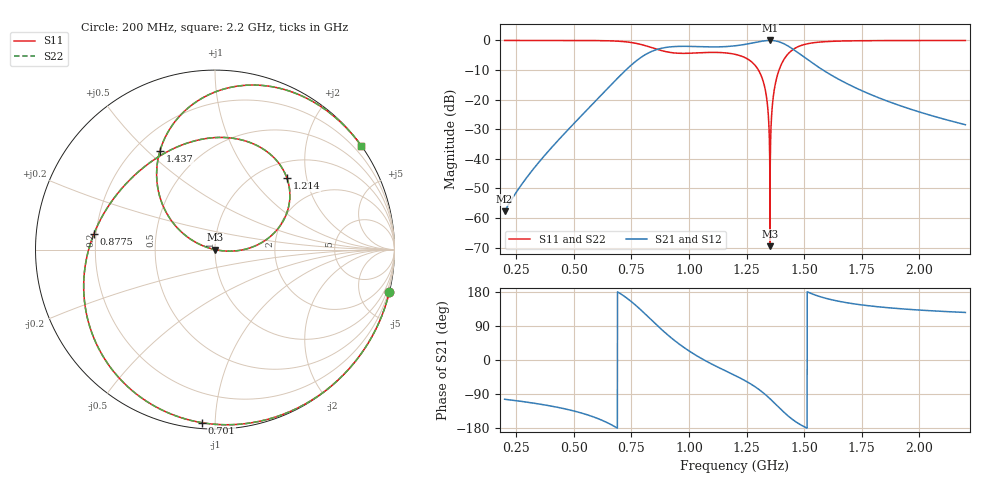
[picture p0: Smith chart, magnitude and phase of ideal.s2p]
! SIMULATED ideal lumped circuit; not measured
# Hz S RI R 50
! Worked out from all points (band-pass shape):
!   4001 points, 200 MHz to 2.2 GHz, reference 50 ohm
!   highest |S21| = 0.00 dB at 1.352 GHz (marker M1); lowest = -57.7 dB at 200 MHz (marker M2)
!   |S21| within 3 dB of the highest: 863.2 MHz to 1.453 GHz (589.5 MHz wide, 50.9 % of centre)
!   lowest |S11| = -69.5 dB at 1.352 GHz (marker M3), VSWR 1.00, Z = 50 + j0.0071 ohm
!   |S11| at or under -10 dB: 1.302 GHz to 1.391 GHz (89.49 MHz wide, 6.65 % of centre)
!   |S22| runs from -69.5 to 0.0 dB; largest |S21 - S12| = 1e-13
!   S11 on the Smith chart (normalised r, x): 200 MHz: 0.00, -8.42; 701 MHz: 0.03, -0.93; 877.5 MHz: 0.19, +0.06; 1.214 GHz: 1.31, +1.54; 1.437 GHz: 0.30, +0.55; 2.2 GHz: 0.00, +3.13
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2e8  0.9722 -0.2343  -0.000304 -0.00126  -0.000304 -0.00126  0.9722 -0.2343
5.335e8  0.6431 -0.7639  -0.041 -0.0345  -0.041 -0.0345  0.6431 -0.7639
7.01e8  -0.0716 -0.9646  -0.253 0.0188  -0.253 0.0188  -0.0716 -0.9646
7.92e8  -0.6375 -0.5708  -0.3451 0.3855  -0.3451 0.3855  -0.6375 -0.5708
8.67e8  -0.6988 0.0185  0.0189 0.7149  0.0189 0.7149  -0.6988 0.0185
8.775e8  -0.6747 0.0877  0.0945 0.7268  0.0945 0.7268  -0.6747 0.0877
9.48e8  -0.4426 0.4194  0.5451 0.5753  0.5451 0.5753  -0.4426 0.4194
1.012e9  -0.2027 0.5755  0.7473 0.2632  0.7473 0.2632  -0.2027 0.5755
1.2e9  0.3813 0.4419  0.6148 -0.5305  0.6148 -0.5305  0.3813 0.4419
1.214e9  0.4003 0.3997  0.5826 -0.5836  0.5826 -0.5836  0.4003 0.3997
1.313e9  0.2554 0.0362  0.1354 -0.9566  0.1354 -0.9566  0.2554 0.0362
1.333e9  0.1363 -0.00449  -0.0326 -0.9901  -0.0326 -0.9901  0.1363 -0.00449
1.345e9  0.0517 -0.00758  -0.145 -0.9881  -0.145 -0.9881  0.0517 -0.00758
1.352e9  -0.000327 7.11e-05  -0.2126 -0.9772  -0.2126 -0.9772  -0.000327 7.11e-05
1.359e9  -0.0527 0.0154  -0.2801 -0.9584  -0.2801 -0.9584  -0.0527 0.0154
1.3685e9  -0.122 0.049  -0.3694 -0.9199  -0.3694 -0.9199  -0.122 0.049
1.381e9  -0.204 0.1147  -0.4765 -0.8474  -0.4765 -0.8474  -0.204 0.1147
1.437e9  -0.3065 0.5507  -0.6785 -0.3776  -0.6785 -0.3776  -0.3065 0.5507
1.5335e9  0.0823 0.903  -0.42 0.0383  -0.42 0.0383  0.0823 0.903
1.6685e9  0.4461 0.8719  -0.1799 0.0921  -0.1799 0.0921  0.4461 0.8719
1.867e9  0.6687 0.7377  -0.0687 0.0622  -0.0687 0.0622  0.6687 0.7377
2.2e9  0.8139 0.5798  -0.0219 0.0307  -0.0219 0.0307  0.8139 0.5798
